VERSION 5.7 ;
BUSBITCHARS "[]" ;
DIVIDERCHAR "/" ;

PROPERTYDEFINITIONS
  LAYER LEF58_TYPE STRING ;
  LAYER LEF58_ENCLOSURE STRING ;
  LAYER LEF58_WIDTH STRING ;
  LAYER LEF58_SPACING STRING ;
END PROPERTYDEFINITIONS

UNITS
  DATABASE MICRONS 1000 ;
END UNITS
MANUFACTURINGGRID 0.001 ;
SITE core9
  CLASS CORE ;
  SYMMETRY Y ;
  SIZE 0.2 BY 1.8 ;
END core9

LAYER OVERLAP
  TYPE OVERLAP ;
END OVERLAP

LAYER ACT
  TYPE MASTERSLICE ;
  PROPERTY LEF58_TYPE "TYPE DIFFUSION ;" ;
  PROPERTY LEF58_WIDTH "WIDTH 0.08 ;" ;
END ACT

LAYER DNW
  TYPE MASTERSLICE ;
  PROPERTY LEF58_TYPE "TYPE PWELL ;" ;
  PROPERTY LEF58_SPACING "SPACING 3.5 ;" ;
  PROPERTY LEF58_WIDTH "WIDTH 3 ;" ;
END DNW

LAYER NW1
  TYPE MASTERSLICE ;
  PROPERTY LEF58_TYPE "TYPE NWELL ;" ;
  PROPERTY LEF58_ENCLOSURE "ENCLOSURE 1 LAYER DNW ;" ;
  PROPERTY LEF58_WIDTH "WIDTH 0.47 ;" ;
END NW1

LAYER POLY
### update by jianfei
#  TYPE ROUTING ;
    TYPE MASTERSLICE ;
#  DIRECTION HORIZONTAL ;
  WIDTH 0.06 ;
#  AREA 0.04 ;
#  SPACING 0.12 ;
#  PROPERTY LEF58_TYPE "TYPE POLYROUTING ;" ;
  PROPERTY LEF58_TYPE "TYPE DIFFUSION ;" ;
END POLY

LAYER NP
  TYPE IMPLANT ;
  WIDTH 0.18 ;
  SPACING 0.18 ;
  AREA 0.12 ;
END NP

LAYER PP
  TYPE IMPLANT ;
  WIDTH 0.18 ;
  SPACING 0.18 ;
  AREA 0.12 ;
END PP

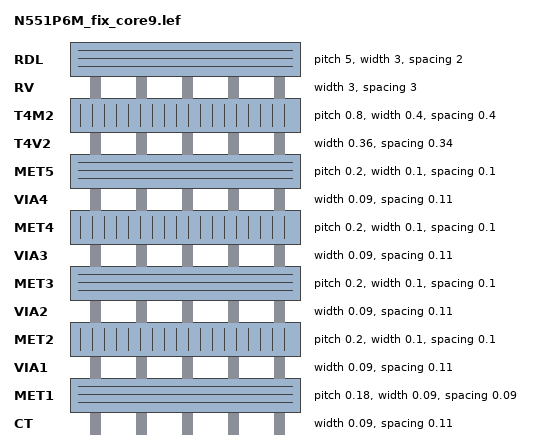
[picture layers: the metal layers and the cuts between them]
LAYER CT
  TYPE CUT ;
  SPACING 0.11 ;
  WIDTH 0.09 ;
  ENCLOSURE ABOVE 0.04 0 ;
  DCCURRENTDENSITY AVERAGE 0.29 ;
END CT

LAYER MET1
  TYPE ROUTING ;
  DIRECTION HORIZONTAL ;
  PITCH 0.18 0.18 ;
  WIDTH 0.09 ;
  OFFSET 0 0 ;
  AREA 0.042 ;
  SPACING 0.09 ;
  MAXWIDTH 10 ;
  MINENCLOSEDAREA 0.18 ;
  RESISTANCE RPERSQ 0.1122 ;
  DCCURRENTDENSITY AVERAGE 1.5 ;
END MET1

LAYER VIA1
  TYPE CUT ;
  SPACING 0.11 ;
  WIDTH 0.09 ;
  DCCURRENTDENSITY AVERAGE 0.135 ;
END VIA1

LAYER MET2
  TYPE ROUTING ;
  DIRECTION VERTICAL ;
  PITCH 0.2 0.2 ;
  WIDTH 0.1 ;
  OFFSET 0 0 ;
  AREA 0.052 ;
  SPACING 0.1 ;
  MAXWIDTH 10 ;
  MINENCLOSEDAREA 0.18 ;
  RESISTANCE RPERSQ 0.0914 ;
  DCCURRENTDENSITY AVERAGE 1.7 ;
END MET2

LAYER VIA2
  TYPE CUT ;
  SPACING 0.11 ;
  WIDTH 0.09 ;
  DCCURRENTDENSITY AVERAGE 0.135 ;
END VIA2

LAYER MET3
  TYPE ROUTING ;
  DIRECTION HORIZONTAL ;
  PITCH 0.2 0.2 ;
  WIDTH 0.1 ;
  OFFSET 0 0 ;
  AREA 0.052 ;
  SPACING 0.1 ;
  MAXWIDTH 10 ;
  MINENCLOSEDAREA 0.18 ;
  RESISTANCE RPERSQ 0.0914 ;
  DCCURRENTDENSITY AVERAGE 1.7 ;
END MET3

LAYER VIA3
  TYPE CUT ;
  SPACING 0.11 ;
  WIDTH 0.09 ;
  DCCURRENTDENSITY AVERAGE 0.135 ;
END VIA3

LAYER MET4
  TYPE ROUTING ;
  DIRECTION VERTICAL ;
  PITCH 0.2 0.2 ;
  WIDTH 0.1 ;
  OFFSET 0 0 ;
  AREA 0.052 ;
  SPACING 0.1 ;
  MAXWIDTH 10 ;
  MINENCLOSEDAREA 0.18 ;
  RESISTANCE RPERSQ 0.0914 ;
  DCCURRENTDENSITY AVERAGE 1.7 ;
END MET4

LAYER VIA4
  TYPE CUT ;
  SPACING 0.11 ;
  WIDTH 0.09 ;
  ENCLOSURE BELOW 0.02 0.005 ;
  DCCURRENTDENSITY AVERAGE 0.135 ;
END VIA4

LAYER MET5
  TYPE ROUTING ;
  DIRECTION HORIZONTAL ;
  PITCH 0.2 0.2 ;
  WIDTH 0.1 ;
  OFFSET 0 0 ;
  AREA 0.052 ;
  SPACING 0.1 ;
  MAXWIDTH 10 ;
  MINENCLOSEDAREA 0.18 ;
  RESISTANCE RPERSQ 0.0914 ;
  DCCURRENTDENSITY AVERAGE 1.7 ;
END MET5

LAYER T4V2
  TYPE CUT ;
  SPACING 0.34 ;
  WIDTH 0.36 ;
  ENCLOSURE BELOW 0.02 0.02 ;
  DCCURRENTDENSITY AVERAGE 3.2 ;
END T4V2

LAYER T4M2
  TYPE ROUTING ;
  DIRECTION VERTICAL ;
  PITCH 0.8 0.8 ;
  WIDTH 0.4 ;
  OFFSET 0 0 ;
  AREA 0.4 ;
  SPACING 0.4 ;
  MAXWIDTH 20 ;
  MINENCLOSEDAREA 0.6 ;
  RESISTANCE RPERSQ 0.0239 ;
  DCCURRENTDENSITY AVERAGE 8.1 ;
END T4M2

LAYER RV
  TYPE CUT ;
  SPACING 3 ;
  WIDTH 3 ;
  ENCLOSURE BELOW 1.5 1.5 ;
  ENCLOSURE ABOVE 1.5 1.5 ;
END RV

LAYER RDL
  TYPE ROUTING ;
  DIRECTION HORIZONTAL ;
  PITCH 5 5 ;
  WIDTH 3 ;
  OFFSET 0 0 ;
  SPACING 2 ;
  RESISTANCE RPERSQ 0.0151 ;
END RDL

VIARULE MET1_SUB GENERATE
  LAYER ACT ;
    ENCLOSURE 0.03 0.03 ;
  LAYER MET1 ;
    ENCLOSURE 0.025 0 ;
  LAYER CT ;
    RECT -0.045 -0.045 0.045 0.045 ;
    SPACING 0.2 BY 0.2 ;
END MET1_SUB

VIARULE MET1_NW1 GENERATE
  LAYER ACT ;
    ENCLOSURE 0.03 0.03 ;
  LAYER MET1 ;
    ENCLOSURE 0.025 0 ;
  LAYER CT ;
    RECT -0.045 -0.045 0.045 0.045 ;
    SPACING 0.2 BY 0.2 ;
END MET1_NW1

VIARULE MET1_PP GENERATE
  LAYER ACT ;
    ENCLOSURE 0.03 0.03 ;
  LAYER MET1 ;
    ENCLOSURE 0.025 0 ;
  LAYER CT ;
    RECT -0.045 -0.045 0.045 0.045 ;
    SPACING 0.2 BY 0.2 ;
END MET1_PP

VIARULE MET1_NP GENERATE
  LAYER ACT ;
    ENCLOSURE 0.03 0.03 ;
  LAYER MET1 ;
    ENCLOSURE 0.025 0 ;
  LAYER CT ;
    RECT -0.045 -0.045 0.045 0.045 ;
    SPACING 0.2 BY 0.2 ;
END MET1_NP

VIARULE MET1_ACT GENERATE
  LAYER ACT ;
    ENCLOSURE 0.03 0.03 ;
  LAYER MET1 ;
    ENCLOSURE 0.025 0 ;
  LAYER CT ;
    RECT -0.045 -0.045 0.045 0.045 ;
    SPACING 0.2 BY 0.2 ;
END MET1_ACT

VIARULE MET1_POLY GENERATE
  LAYER POLY ;
    ENCLOSURE 0.04 0.04 ;
  LAYER MET1 ;
    ENCLOSURE 0.025 0 ;
  LAYER CT ;
    RECT -0.045 -0.045 0.045 0.045 ;
    SPACING 0.2 BY 0.2 ;
END MET1_POLY

VIARULE MET2_MET1 GENERATE DEFAULT
  LAYER MET1 ;
    ENCLOSURE 0.03 0 ;
  LAYER MET2 ;
    ENCLOSURE 0.02 0.005 ;
  LAYER VIA1 ;
    RECT -0.045 -0.045 0.045 0.045 ;
    SPACING 0.2 BY 0.2 ;
END MET2_MET1

VIARULE MET3_MET2 GENERATE DEFAULT
  LAYER MET2 ;
    ENCLOSURE 0.03 0.005 ;
  LAYER MET3 ;
    ENCLOSURE 0.02 0.005 ;
  LAYER VIA2 ;
    RECT -0.045 -0.045 0.045 0.045 ;
    SPACING 0.2 BY 0.2 ;
END MET3_MET2

VIARULE MET4_MET3 GENERATE DEFAULT
  LAYER MET3 ;
    ENCLOSURE 0.03 0.005 ;
  LAYER MET4 ;
    ENCLOSURE 0.02 0.005 ;
  LAYER VIA3 ;
    RECT -0.045 -0.045 0.045 0.045 ;
    SPACING 0.2 BY 0.2 ;
END MET4_MET3

VIARULE MET5_MET4 GENERATE DEFAULT
  LAYER MET4 ;
    ENCLOSURE 0.03 0.005 ;
  LAYER MET5 ;
    ENCLOSURE 0.02 0.005 ;
  LAYER VIA4 ;
    RECT -0.045 -0.045 0.045 0.045 ;
    SPACING 0.2 BY 0.2 ;
END MET5_MET4

VIARULE T4M2_MET5 GENERATE DEFAULT
  LAYER MET5 ;
    ENCLOSURE 0.01 0.05 ;
  LAYER T4M2 ;
    ENCLOSURE 0.02 0.02 ;
  LAYER T4V2 ;
    RECT -0.18 -0.18 0.18 0.18 ;
    SPACING 0.7 BY 0.7 ;
END T4M2_MET5

VIARULE RDL_T4M2 GENERATE DEFAULT
  LAYER T4M2 ;
    ENCLOSURE 1.5 1.5 ;
  LAYER RDL ;
    ENCLOSURE 1.5 1.5 ;
  LAYER RV ;
    RECT -1.5 -1.5 1.5 1.5 ;
    SPACING 6 BY 6 ;
END RDL_T4M2

#NONDEFAULTRULE virtuosoDefaultTaper
#  LAYER POLY
#    WIDTH 0.06 ;
#  END POLY
#  LAYER MET1
#    WIDTH 0.09 ;
#  END MET1
#  USEVIARULE MET1_POLY ;
#END virtuosoDefaultTaper
END LIBRARY
